###############################################################
#  Generated by:      Cadence Innovus 20.13-s083_1
#  OS:                Linux x86_64(Host ID rice-503-20-north)
#  Generated on:      Tue May 17 01:02:42 2022
#  Design:            ringosc
#  Command:           write_lef_abstract -specifyTopLayer 6 -PGPinLayers {5 6} -noCutObs -stripePin results/ringosc.lef
###############################################################

VERSION 5.8 ;

BUSBITCHARS "[]" ;
DIVIDERCHAR "/" ;

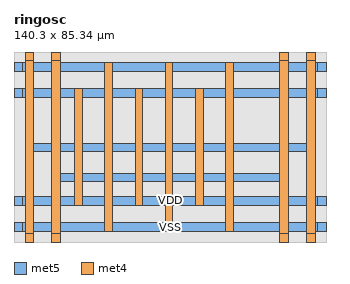
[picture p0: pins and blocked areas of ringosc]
MACRO ringosc
  CLASS BLOCK ;
  SIZE 140.300000 BY 85.340000 ;
  FOREIGN ringosc 0.000000 0.000000 ;
  ORIGIN 0 0 ;
  SYMMETRY X Y R90 ;
  PIN VSS
    DIRECTION INOUT ;
    USE GROUND ;
    PORT
      LAYER met5 ;
        RECT 136.300000 76.760000 140.300000 80.760000 ;
    END
    PORT
      LAYER met5 ;
        RECT 0.000000 76.760000 4.000000 80.760000 ;
    END
    PORT
      LAYER met5 ;
        RECT 136.300000 4.560000 140.300000 8.560000 ;
    END
    PORT
      LAYER met5 ;
        RECT 0.000000 4.560000 4.000000 8.560000 ;
    END
    PORT
      LAYER met4 ;
        RECT 131.300000 81.340000 135.300000 85.340000 ;
    END
    PORT
      LAYER met4 ;
        RECT 131.300000 0.000000 135.300000 4.000000 ;
    END
    PORT
      LAYER met4 ;
        RECT 4.980000 81.340000 8.980000 85.340000 ;
    END
    PORT
      LAYER met4 ;
        RECT 4.980000 0.000000 8.980000 4.000000 ;
    END

# P/G power stripe data as pin
    PORT
      LAYER met4 ;
        RECT 95.200000 4.560000 98.560000 80.760000 ;
        RECT 68.000000 4.560000 71.360000 80.760000 ;
        RECT 40.800000 4.560000 44.160000 80.760000 ;
        RECT 131.300000 0.000000 135.300000 85.340000 ;
        RECT 4.980000 0.000000 8.980000 85.340000 ;
      LAYER met5 ;
        RECT 4.980000 40.800000 135.300000 44.160000 ;
        RECT 0.000000 4.560000 140.300000 8.560000 ;
        RECT 0.000000 76.760000 140.300000 80.760000 ;
    END
# end of P/G power stripe data as pin

  END VSS
  PIN VDD
    DIRECTION INOUT ;
    USE POWER ;
    PORT
      LAYER met5 ;
        RECT 136.300000 64.760000 140.300000 68.760000 ;
    END
    PORT
      LAYER met5 ;
        RECT 0.000000 64.760000 4.000000 68.760000 ;
    END
    PORT
      LAYER met5 ;
        RECT 136.300000 16.560000 140.300000 20.560000 ;
    END
    PORT
      LAYER met5 ;
        RECT 0.000000 16.560000 4.000000 20.560000 ;
    END
    PORT
      LAYER met4 ;
        RECT 119.300000 81.340000 123.300000 85.340000 ;
    END
    PORT
      LAYER met4 ;
        RECT 119.300000 0.000000 123.300000 4.000000 ;
    END
    PORT
      LAYER met4 ;
        RECT 16.980000 81.340000 20.980000 85.340000 ;
    END
    PORT
      LAYER met4 ;
        RECT 16.980000 0.000000 20.980000 4.000000 ;
    END

# P/G power stripe data as pin
    PORT
      LAYER met4 ;
        RECT 81.600000 16.560000 84.960000 68.760000 ;
        RECT 54.400000 16.560000 57.760000 68.760000 ;
        RECT 27.200000 16.560000 30.560000 68.760000 ;
        RECT 119.300000 0.000000 123.300000 85.340000 ;
        RECT 16.980000 0.000000 20.980000 85.340000 ;
      LAYER met5 ;
        RECT 16.980000 27.200000 123.300000 30.560000 ;
        RECT 0.000000 16.560000 140.300000 20.560000 ;
        RECT 0.000000 64.760000 140.300000 68.760000 ;
    END
# end of P/G power stripe data as pin

  END VDD
  OBS
    LAYER li1 ;
      RECT 0.000000 0.000000 140.300000 85.340000 ;
    LAYER met1 ;
      RECT 0.000000 0.000000 140.300000 85.340000 ;
    LAYER met2 ;
      RECT 0.000000 0.000000 140.300000 85.340000 ;
    LAYER met3 ;
      RECT 0.000000 0.000000 140.300000 85.340000 ;
    LAYER met4 ;
      RECT 0.000000 0.000000 140.300000 85.340000 ;
    LAYER met5 ;
      RECT 0.000000 0.000000 140.300000 85.340000 ;
  END
END ringosc

END LIBRARY
